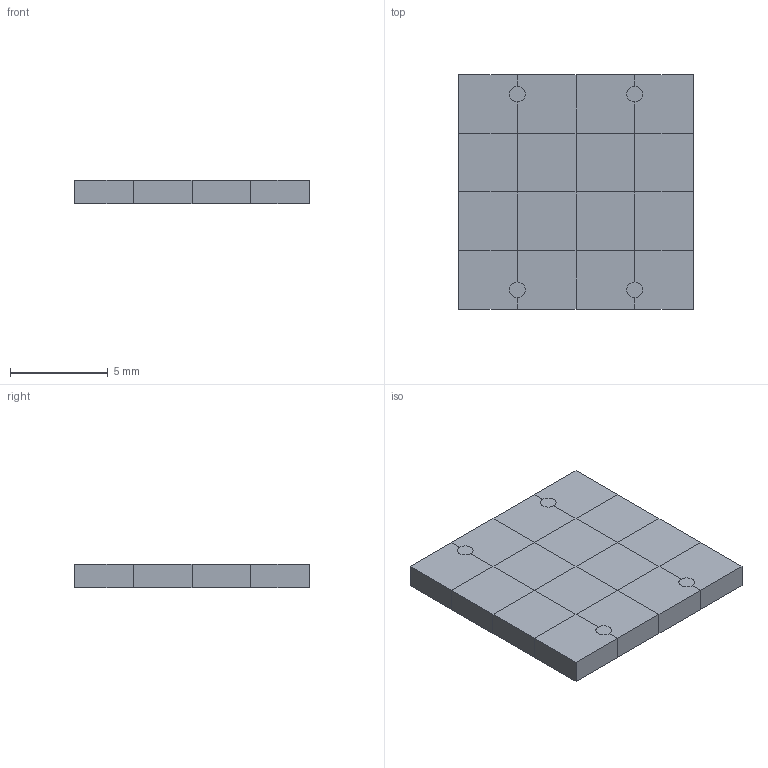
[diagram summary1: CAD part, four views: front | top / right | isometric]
STEP (ISO 10303-21) file: header records copied from the file, then geometry measured from it (millimetres).
FILE_DESCRIPTION(('Open CASCADE Model'),'2;1');
FILE_NAME('Open CASCADE Shape Model','2026-11-20T12:56:39',('Author'),( 'Open CASCADE'),'Open CASCADE STEP processor 7.9','Open CASCADE 7.9' ,'Unknown');
FILE_SCHEMA(('AUTOMOTIVE_DESIGN { 1 0 10303 214 1 1 1 1 }'));
Length unit declared in the file: millimetre
Products named in the file (3): manifold_AD_33-34_1; fluid; solid
Assembly tree (2 placements, depth 2):
  manifold_AD_33-34_1
    fluid
    solid
Bounding box: 12 x 12 x 1.2 mm (x, y, z)
Volume: 172.8 mm3; surface area: 1400.3 mm2
Topology: 2 solids, 2 shells, 1208 faces, 4296 edges, 2418 vertices
Faces by surface type: plane 1200, cylinder 8
Full cylindrical faces by diameter (mm): 0.8 x8
Entity records: 100654 total; most frequent: CARTESIAN_POINT 16565, DIRECTION 15326, LINE 12840, VECTOR 12840, ORIENTED_EDGE 8592, PCURVE 8592, DEFINITIONAL_REPRESENTATION 8592, EDGE_CURVE 4296
One B-rep face of a CAD part: STEP entity #53742.
In plain terms, the planar face has unit normal (0, 0, 1).
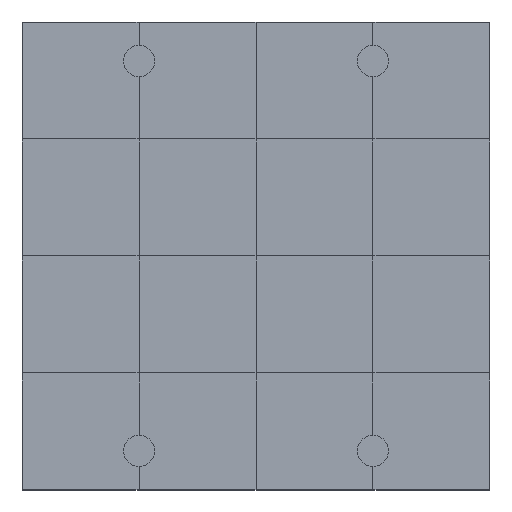
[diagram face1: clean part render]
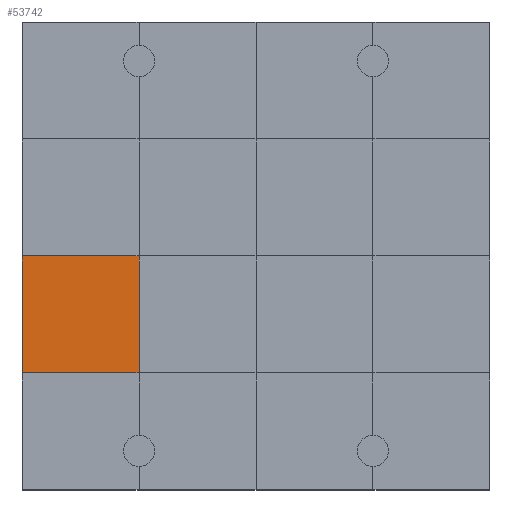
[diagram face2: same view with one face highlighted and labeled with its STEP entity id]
Its self-contained STEP definition (entity closure, numbers rounded to 3 decimals):
#53292 = VERTEX_POINT('',#53293);
#53293 = CARTESIAN_POINT('',(0.,3.,1.2));
#53307 = PLANE('',#53308);
#53308 = AXIS2_PLACEMENT_3D('',#53309,#53310,#53311);
#53309 = CARTESIAN_POINT('',(0.,3.,0.));
#53310 = DIRECTION('',(1.,0.,-0.));
#53311 = DIRECTION('',(0.,0.,1.));
#53333 = PLANE('',#53334);
#53334 = AXIS2_PLACEMENT_3D('',#53335,#53336,#53337);
#53335 = CARTESIAN_POINT('',(0.,0.,1.2));
#53336 = DIRECTION('',(0.,0.,1.));
#53337 = DIRECTION('',(1.,0.,-0.));
#53484 = VERTEX_POINT('',#53485);
#53485 = CARTESIAN_POINT('',(3.,3.,1.2));
#53506 = EDGE_CURVE('',#53292,#53484,#53507,.T.);
#53507 = SURFACE_CURVE('',#53508,(#53512,#53519),.PCURVE_S1.);
#53508 = LINE('',#53509,#53510);
#53509 = CARTESIAN_POINT('',(0.,3.,1.2));
#53510 = VECTOR('',#53511,1.);
#53511 = DIRECTION('',(1.,0.,-0.));
#53512 = PCURVE('',#53333,#53513);
#53513 = DEFINITIONAL_REPRESENTATION('',(#53514),#53518);
#53514 = LINE('',#53515,#53516);
#53515 = CARTESIAN_POINT('',(0.,3.));
#53516 = VECTOR('',#53517,1.);
#53517 = DIRECTION('',(1.,0.));
#53518 = ( GEOMETRIC_REPRESENTATION_CONTEXT(2) 
PARAMETRIC_REPRESENTATION_CONTEXT() REPRESENTATION_CONTEXT('2D SPACE',''
  ) );
#53519 = PCURVE('',#53520,#53525);
#53520 = PLANE('',#53521);
#53521 = AXIS2_PLACEMENT_3D('',#53522,#53523,#53524);
#53522 = CARTESIAN_POINT('',(0.,3.,1.2));
#53523 = DIRECTION('',(0.,0.,1.));
#53524 = DIRECTION('',(1.,0.,-0.));
#53525 = DEFINITIONAL_REPRESENTATION('',(#53526),#53530);
#53526 = LINE('',#53527,#53528);
#53527 = CARTESIAN_POINT('',(0.,0.));
#53528 = VECTOR('',#53529,1.);
#53529 = DIRECTION('',(1.,0.));
#53530 = ( GEOMETRIC_REPRESENTATION_CONTEXT(2) 
PARAMETRIC_REPRESENTATION_CONTEXT() REPRESENTATION_CONTEXT('2D SPACE',''
  ) );
#53565 = VERTEX_POINT('',#53566);
#53566 = CARTESIAN_POINT('',(0.,6.,1.2));
#53592 = EDGE_CURVE('',#53292,#53565,#53593,.T.);
#53593 = SURFACE_CURVE('',#53594,(#53598,#53605),.PCURVE_S1.);
#53594 = LINE('',#53595,#53596);
#53595 = CARTESIAN_POINT('',(0.,3.,1.2));
#53596 = VECTOR('',#53597,1.);
#53597 = DIRECTION('',(-0.,1.,0.));
#53598 = PCURVE('',#53307,#53599);
#53599 = DEFINITIONAL_REPRESENTATION('',(#53600),#53604);
#53600 = LINE('',#53601,#53602);
#53601 = CARTESIAN_POINT('',(1.2,0.));
#53602 = VECTOR('',#53603,1.);
#53603 = DIRECTION('',(0.,-1.));
#53604 = ( GEOMETRIC_REPRESENTATION_CONTEXT(2) 
PARAMETRIC_REPRESENTATION_CONTEXT() REPRESENTATION_CONTEXT('2D SPACE',''
  ) );
#53605 = PCURVE('',#53520,#53606);
#53606 = DEFINITIONAL_REPRESENTATION('',(#53607),#53611);
#53607 = LINE('',#53608,#53609);
#53608 = CARTESIAN_POINT('',(0.,0.));
#53609 = VECTOR('',#53610,1.);
#53610 = DIRECTION('',(0.,1.));
#53611 = ( GEOMETRIC_REPRESENTATION_CONTEXT(2) 
PARAMETRIC_REPRESENTATION_CONTEXT() REPRESENTATION_CONTEXT('2D SPACE',''
  ) );
#53742 = ADVANCED_FACE('',(#53743),#53520,.T.);
#53743 = FACE_BOUND('',#53744,.T.);
#53744 = EDGE_LOOP('',(#53745,#53746,#53747,#53775));
#53745 = ORIENTED_EDGE('',*,*,#53592,.F.);
#53746 = ORIENTED_EDGE('',*,*,#53506,.T.);
#53747 = ORIENTED_EDGE('',*,*,#53748,.T.);
#53748 = EDGE_CURVE('',#53484,#53749,#53751,.T.);
#53749 = VERTEX_POINT('',#53750);
#53750 = CARTESIAN_POINT('',(3.,6.,1.2));
#53751 = SURFACE_CURVE('',#53752,(#53756,#53763),.PCURVE_S1.);
#53752 = LINE('',#53753,#53754);
#53753 = CARTESIAN_POINT('',(3.,3.,1.2));
#53754 = VECTOR('',#53755,1.);
#53755 = DIRECTION('',(-0.,1.,0.));
#53756 = PCURVE('',#53520,#53757);
#53757 = DEFINITIONAL_REPRESENTATION('',(#53758),#53762);
#53758 = LINE('',#53759,#53760);
#53759 = CARTESIAN_POINT('',(3.,0.));
#53760 = VECTOR('',#53761,1.);
#53761 = DIRECTION('',(0.,1.));
#53762 = ( GEOMETRIC_REPRESENTATION_CONTEXT(2) 
PARAMETRIC_REPRESENTATION_CONTEXT() REPRESENTATION_CONTEXT('2D SPACE',''
  ) );
#53763 = PCURVE('',#53764,#53769);
#53764 = PLANE('',#53765);
#53765 = AXIS2_PLACEMENT_3D('',#53766,#53767,#53768);
#53766 = CARTESIAN_POINT('',(3.,3.,1.2));
#53767 = DIRECTION('',(0.,0.,1.));
#53768 = DIRECTION('',(1.,0.,-0.));
#53769 = DEFINITIONAL_REPRESENTATION('',(#53770),#53774);
#53770 = LINE('',#53771,#53772);
#53771 = CARTESIAN_POINT('',(0.,0.));
#53772 = VECTOR('',#53773,1.);
#53773 = DIRECTION('',(0.,1.));
#53774 = ( GEOMETRIC_REPRESENTATION_CONTEXT(2) 
PARAMETRIC_REPRESENTATION_CONTEXT() REPRESENTATION_CONTEXT('2D SPACE',''
  ) );
#53775 = ORIENTED_EDGE('',*,*,#53776,.F.);
#53776 = EDGE_CURVE('',#53565,#53749,#53777,.T.);
#53777 = SURFACE_CURVE('',#53778,(#53782,#53789),.PCURVE_S1.);
#53778 = LINE('',#53779,#53780);
#53779 = CARTESIAN_POINT('',(0.,6.,1.2));
#53780 = VECTOR('',#53781,1.);
#53781 = DIRECTION('',(1.,0.,-0.));
#53782 = PCURVE('',#53520,#53783);
#53783 = DEFINITIONAL_REPRESENTATION('',(#53784),#53788);
#53784 = LINE('',#53785,#53786);
#53785 = CARTESIAN_POINT('',(0.,3.));
#53786 = VECTOR('',#53787,1.);
#53787 = DIRECTION('',(1.,0.));
#53788 = ( GEOMETRIC_REPRESENTATION_CONTEXT(2) 
PARAMETRIC_REPRESENTATION_CONTEXT() REPRESENTATION_CONTEXT('2D SPACE',''
  ) );
#53789 = PCURVE('',#53790,#53795);
#53790 = PLANE('',#53791);
#53791 = AXIS2_PLACEMENT_3D('',#53792,#53793,#53794);
#53792 = CARTESIAN_POINT('',(0.,6.,1.2));
#53793 = DIRECTION('',(0.,0.,1.));
#53794 = DIRECTION('',(1.,0.,-0.));
#53795 = DEFINITIONAL_REPRESENTATION('',(#53796),#53800);
#53796 = LINE('',#53797,#53798);
#53797 = CARTESIAN_POINT('',(0.,0.));
#53798 = VECTOR('',#53799,1.);
#53799 = DIRECTION('',(1.,0.));
#53800 = ( GEOMETRIC_REPRESENTATION_CONTEXT(2) 
PARAMETRIC_REPRESENTATION_CONTEXT() REPRESENTATION_CONTEXT('2D SPACE',''
  ) );
